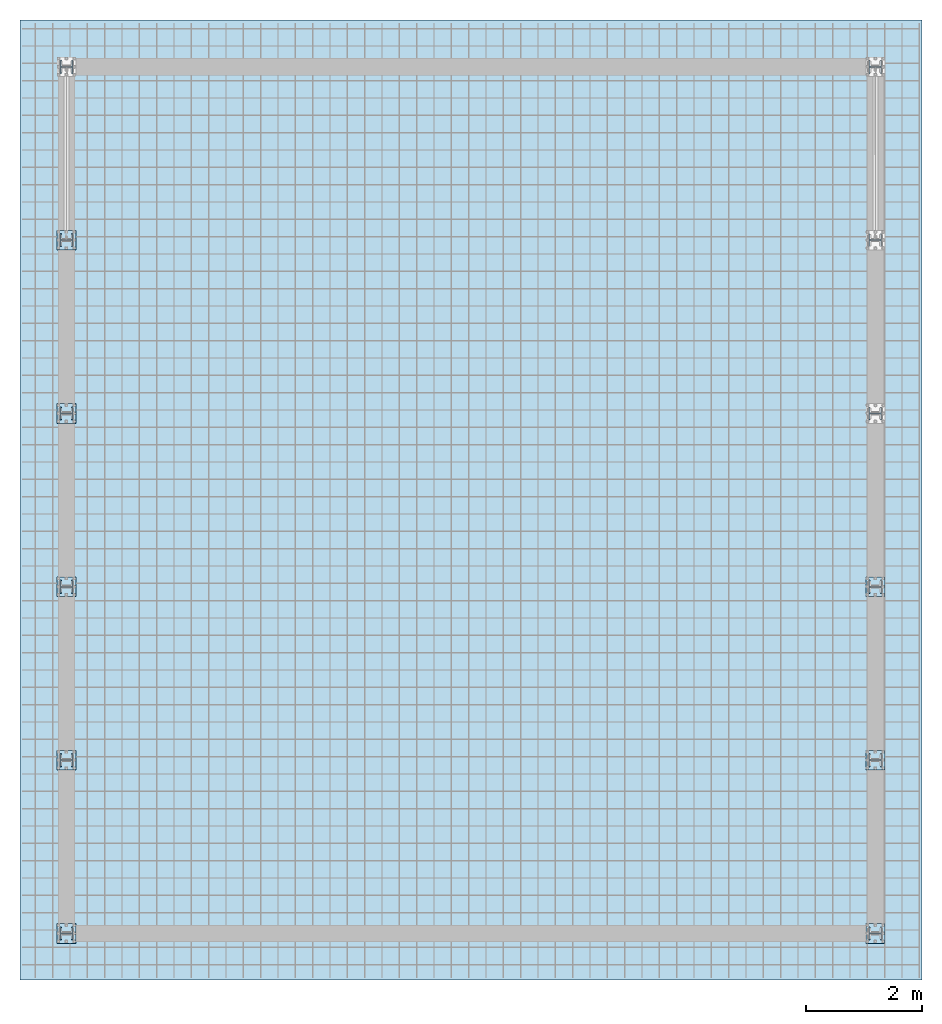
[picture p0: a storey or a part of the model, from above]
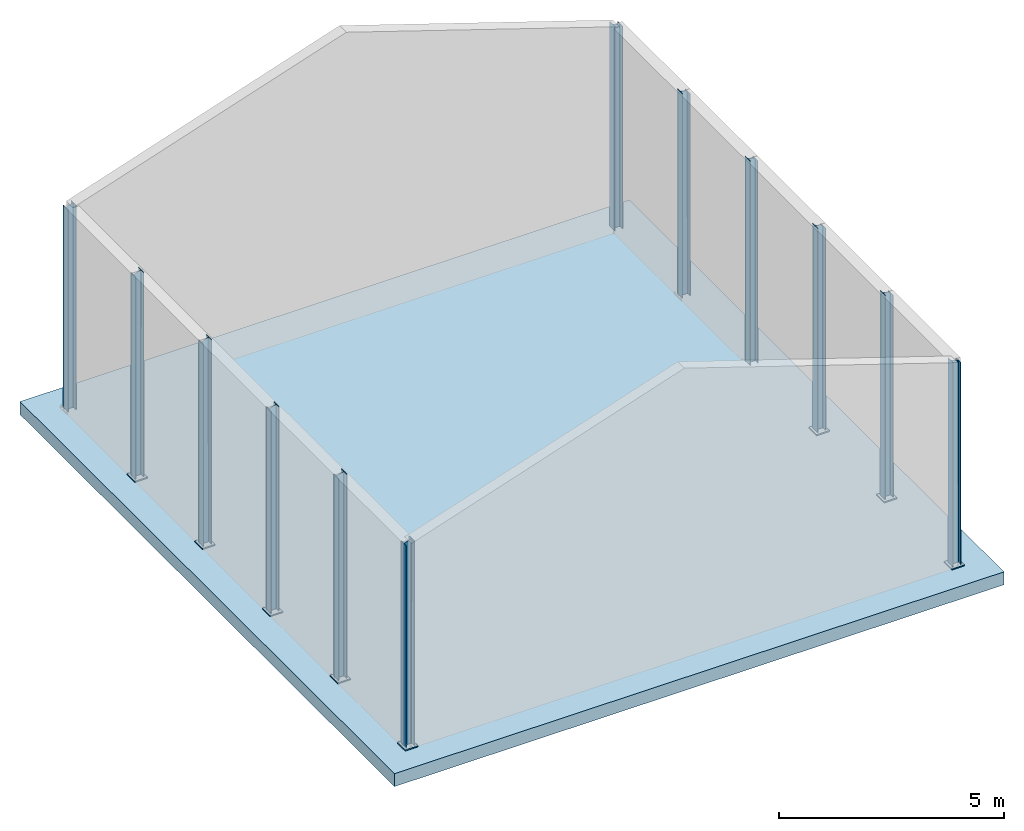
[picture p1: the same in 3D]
Properties of the parts of a building model (IFC4), part 1 of 2

# File
Description: ViewDefinition [CoordinationView]
Made in: IFC file generated by ModeSt (Tecnisoft s.a.s.)

# IfcBuildingStorey (2)
In: Capannone
Name | Elevation (m)
Storey 0 | 0
Storey 1 | 5.55

# IfcBeam: 3 IPE240 (96)
In: Storey 1
Type - PredefinedType: BEAM; Material: Acciaio
Description: 3 IPE240 - Acciaio
Pset_BeamCommon - LoadBearing: yes
BaseQuantities - ?: 0.00371848 m2
Name | BaseQuantities, ? (m3) | BaseQuantities, ? (m)
103 | 0.00313125 | 0.842077
104 | 0.00313125 | 0.842077
101 | 0.00313125 | 0.842077
102 | 0.00313125 | 0.842077
105 | 0.00313125 | 0.842077
106 | 0.00313125 | 0.842077
145 | 0.00313124 | 0.842077
144 | 0.00313124 | 0.842077
143 | 0.00313124 | 0.842077
142 | 0.00313124 | 0.842077
7 x 106 | 0.00391406 | 1.0526
7 x 145 | 0.00391406 | 1.0526
7 x 101 | 0.00391406 | 1.0526
7 x 102 | 0.00391406 | 1.0526
7 x 103 | 0.00391406 | 1.0526
7 x 142 | 0.00391406 | 1.0526
7 x 104 | 0.00391406 | 1.0526
7 x 143 | 0.00391406 | 1.0526
7 x 105 | 0.00391406 | 1.0526
7 x 144 | 0.00391406 | 1.0526
141 | 0.00313124 | 0.842077
140 | 0.00313124 | 0.842077
7 x 141 | 0.00391406 | 1.0526
7 x 140 | 0.00391406 | 1.0526

# IfcBuildingElementProxy: 1 Piatto 50x5 (16)
In: Storey 1
Type - PredefinedType: MEMBER; Material: Acciaio
Description: 1 Piatto 50x5 - Acciaio
Pset_MemberCommon - LoadBearing: yes
BaseQuantities - ?: 0.00025 m2
Name | BaseQuantities, ? (m3) | BaseQuantities, ? (m)
139 | 0.000916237 | 3.66495
135 | 0.000794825 | 3.1793
132 | 0.000794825 | 3.1793
137 | 0.000916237 | 3.66495
126 | 0.000916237 | 3.66495
129 | 0.000916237 | 3.66495
131 | 0.000916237 | 3.66495
127 | 0.000916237 | 3.66495
124 | 0.000916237 | 3.66495
130 | 0.000916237 | 3.66495
134 | 0.000916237 | 3.66495
133 | 0.000794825 | 3.1793
138 | 0.000794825 | 3.1793
136 | 0.000916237 | 3.66495
128 | 0.000916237 | 3.66495
125 | 0.000916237 | 3.66495

# IfcBuildingElementProxy: 2 L45x4 (4)
In: Storey 0
Type - PredefinedType: MEMBER; Material: Acciaio
Description: 2 L45x4 - Acciaio
Pset_MemberCommon - LoadBearing: yes
BaseQuantities - ?: 0.000344 m2; ?: 0.00217027 m3; ?: 6.30892 m
Name
200
186
147
161

# IfcBuildingElementProxy: 4 RHS100x50x3.2 (119)
In: Storey 1
Type - PredefinedType: MEMBER; Material: Acciaio
Description: 4 RHS100x50x3.2 - Acciaio
Pset_MemberCommon - LoadBearing: yes
BaseQuantities - ?: 0.00091904 m2
Name | BaseQuantities, ? (m3) | BaseQuantities, ? (m)
2 x 115 | 0.000560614 | 0.61
2 x 121 | 0.000560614 | 0.61
2 x 109 | 0.000560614 | 0.61
2 x 114 | 0.000560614 | 0.61
2 x 113 | 0.000560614 | 0.61
2 x 112 | 0.000560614 | 0.61
2 x 111 | 0.000560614 | 0.61
2 x 110 | 0.000560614 | 0.61
2 x 107 | 0.000560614 | 0.61
2 x 108 | 0.000560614 | 0.61
2 x 116 | 0.000560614 | 0.61
5 x 107 | 0.00275712 | 3
2 x 117 | 0.000560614 | 0.61
2 x 118 | 0.000560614 | 0.61
2 x 119 | 0.000560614 | 0.61
2 x 120 | 0.000560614 | 0.61
2 x 123 | 0.000560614 | 0.61
2 x 122 | 0.000560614 | 0.61
5 x 110 | 0.00275712 | 3
5 x 112 | 0.00275712 | 3
5 x 114 | 0.00275712 | 3
5 x 123 | 0.00275712 | 3
5 x 122 | 0.00275712 | 3
5 x 108 | 0.00275712 | 3
5 x 115 | 0.00275712 | 3
5 x 113 | 0.00275712 | 3
5 x 111 | 0.00275712 | 3
5 x 109 | 0.00275712 | 3
5 x 116 | 0.00275712 | 3
5 x 117 | 0.00275712 | 3
5 x 118 | 0.00275712 | 3
5 x 119 | 0.00275712 | 3
5 x 120 | 0.00275712 | 3
5 x 121 | 0.00275712 | 3

# IfcColumn: 5 HEA220 (12)
In: Storey 0
Type - PredefinedType: COLUMN; Material: Acciaio
Description: 5 HEA220 - Acciaio
Pset_ColumnCommon - LoadBearing: yes
BaseQuantities - ?: 0.006156 m2; ?: 0.0341658 m3; ?: 5.55 m
Name
10
4
6
8
9
7
5
3
12
11
1
2

# IfcFastener: Collegamenti -1142_-1128 -1143_-1130 -1144_-1132 -1145_-1134 -1146_-1136 -1147_-1138 (108)
In: Storey 1
Type - PredefinedType: WELD
Name | Description
48 x Collegamenti -1142_-1128 -1143_-1130 -1144_-1132 -1145_-1134 -1146_-1136 -1147_-1138 | 13x13
60 x Collegamenti -1142_-1128 -1143_-1130 -1144_-1132 -1145_-1134 -1146_-1136 -1147_-1138 | 10x10

# IfcFastener: Collegamenti 0001_0101 0002_0102 0003_0103 0004_0104 0005_0105 0006_0106 0007_0107 0008_0108 0009_0109 0010_0110 0011_0111 0012_0112 (192)
In: Storey 0
Type - PredefinedType: WELD
Description: 16x16

# IfcFastener: Collegamenti 0101_0001 0103_0003 0105_0005 0107_0007 0109_0009 0111_0011 (96)
In: Storey 1
Type - PredefinedType: WELD
Description: 10x10

# IfcFastener: Collegamenti 0102_0002 0104_0004 0106_0006 0108_0008 0110_0010 0112_0012 (96)
In: Storey 1
Type - PredefinedType: WELD
Description: 10x10

# IfcFastener: Collegamento -1055_-1089 (2)
In: Storey 1
Type - PredefinedType: WELD
Description: 7x7

# IfcFastener: Collegamento -1055_0111 (2)
In: Storey 1
Type - PredefinedType: WELD
Description: 7x7

# IfcFastener: Collegamento -1056_-1090 (2)
In: Storey 1
Type - PredefinedType: WELD
Description: 7x7

# IfcFastener: Collegamento -1056_0112 (2)
In: Storey 1
Type - PredefinedType: WELD
Description: 7x7

# IfcFastener: Collegamento -1057_-1087 (2)
In: Storey 1
Type - PredefinedType: WELD
Description: 7x7

# IfcFastener: Collegamento -1057_0109 (2)
In: Storey 1
Type - PredefinedType: WELD
Description: 7x7

# IfcFastener: Collegamento -1058_-1088 (2)
In: Storey 1
Type - PredefinedType: WELD
Description: 7x7

# IfcFastener: Collegamento -1058_0110 (2)
In: Storey 1
Type - PredefinedType: WELD
Description: 7x7

# IfcFastener: Collegamento -1087_-1057 (2)
In: Storey 1
Type - PredefinedType: WELD
Description: 7x7

# IfcFastener: Collegamento -1087_-1121 (2)
In: Storey 1
Type - PredefinedType: WELD
Description: 7x7

# IfcFastener: Collegamento -1088_-1058 (2)
In: Storey 1
Type - PredefinedType: WELD
Description: 7x7

# IfcFastener: Collegamento -1088_-1122 (2)
In: Storey 1
Type - PredefinedType: WELD
Description: 7x7

# IfcFastener: Collegamento -1089_-1055 (2)
In: Storey 1
Type - PredefinedType: WELD
Description: 7x7

# IfcFastener: Collegamento -1089_-1119 (2)
In: Storey 1
Type - PredefinedType: WELD
Description: 7x7

# IfcFastener: Collegamento -1090_-1056 (2)
In: Storey 1
Type - PredefinedType: WELD
Description: 7x7

# IfcFastener: Collegamento -1090_-1120 (2)
In: Storey 1
Type - PredefinedType: WELD
Description: 7x7

# IfcFastener: Collegamento -1119_-1089 (2)
In: Storey 1
Type - PredefinedType: WELD
Description: 7x7

# IfcFastener: Collegamento -1119_-1147 (2)
In: Storey 1
Type - PredefinedType: WELD
Description: 7x7

# IfcFastener: Collegamento -1120_-1090 (2)
In: Storey 1
Type - PredefinedType: WELD
Description: 7x7

# IfcFastener: Collegamento -1120_-1147 (2)
In: Storey 1
Type - PredefinedType: WELD
Description: 7x7

# IfcFastener: Collegamento -1121_-1087 (2)
In: Storey 1
Type - PredefinedType: WELD
Description: 7x7

# IfcFastener: Collegamento -1121_-1146 (2)
In: Storey 1
Type - PredefinedType: WELD
Description: 7x7

# IfcFastener: Collegamento -1122_-1088 (2)
In: Storey 1
Type - PredefinedType: WELD
Description: 7x7

# IfcFastener: Collegamento -1122_-1146 (2)
In: Storey 1
Type - PredefinedType: WELD
Description: 7x7

# IfcFastener: Collegamento -1146_-1121 (2)
In: Storey 1
Type - PredefinedType: WELD
Description: 7x7

# IfcFastener: Collegamento -1146_-1122 (2)
In: Storey 1
Type - PredefinedType: WELD
Description: 7x7

# IfcFastener: Collegamento -1147_-1119 (2)
In: Storey 1
Type - PredefinedType: WELD
Description: 7x7

# IfcFastener: Collegamento -1147_-1120 (2)
In: Storey 1
Type - PredefinedType: WELD
Description: 7x7

# IfcFastener: Collegamento 0009_0111 (2)
In: Storey 0
Type - PredefinedType: WELD
Description: 5x5

# IfcFastener: Collegamento 0010_0112 (2)
In: Storey 0
Type - PredefinedType: WELD
Description: 5x5

# IfcFastener: Collegamento 0011_0109 (2)
In: Storey 0
Type - PredefinedType: WELD
Description: 5x5

# IfcFastener: Collegamento 0012_0110 (2)
In: Storey 0
Type - PredefinedType: WELD
Description: 5x5

# IfcFastener: Collegamento 0109_-1057 (2)
In: Storey 1
Type - PredefinedType: WELD
Description: 7x7

# IfcFastener: Collegamento 0109_0011 (2)
In: Storey 1
Type - PredefinedType: WELD
Description: 5x5

# IfcFastener: Collegamento 0110_-1058 (2)
In: Storey 1
Type - PredefinedType: WELD
Description: 7x7

# IfcFastener: Collegamento 0110_0012 (2)
In: Storey 1
Type - PredefinedType: WELD
Description: 5x5

# IfcFastener: Collegamento 0111_-1055 (2)
In: Storey 1
Type - PredefinedType: WELD
Description: 7x7

# IfcFastener: Collegamento 0111_0009 (2)
In: Storey 1
Type - PredefinedType: WELD
Description: 5x5

# IfcFastener: Collegamento 0112_-1056 (2)
In: Storey 1
Type - PredefinedType: WELD
Description: 7x7

# IfcFastener: Collegamento 0112_0010 (2)
In: Storey 1
Type - PredefinedType: WELD
Description: 5x5

# IfcFooting: 1 Platea di fondazione
In: Storey 0
Type - PredefinedType: STRIP_FOOTING
Description: 1 Platea di fondazione; Material: Calcestruzzo classe C25/30 0.35 m
Pset_WallCommon - LoadBearing: yes
BaseQuantities - ?: 90.7761 m3

# IfcMechanicalFastener: Collegamenti -1142_-1128 -1143_-1130 -1144_-1132 -1145_-1134 -1146_-1136 -1147_-1138 (144)
In: Storey 1
Type - PredefinedType: BOLT
Name | Description | NominalDiameter (m)
44 x Collegamenti -1142_-1128 -1143_-1130 -1144_-1132 -1145_-1134 -1146_-1136 -1147_-1138 | M16 | 0.016
36 x Collegamenti -1142_-1128 -1143_-1130 -1144_-1132 -1145_-1134 -1146_-1136 -1147_-1138 | M32 | 0.032
4 x Collegamenti -1142_-1128 -1143_-1130 -1144_-1132 -1145_-1134 -1146_-1136 -1147_-1138 | M16 | 0.0159996
24 x Collegamenti -1142_-1128 -1143_-1130 -1144_-1132 -1145_-1134 -1146_-1136 -1147_-1138 | M16 | 0.0159995
36 x Collegamenti -1142_-1128 -1143_-1130 -1144_-1132 -1145_-1134 -1146_-1136 -1147_-1138 | M16 | 0.0159993

# IfcMechanicalFastener: Collegamenti 0001_0101 0002_0102 0003_0103 0004_0104 0005_0105 0006_0106 0007_0107 0008_0108 0009_0109 0010_0110 0011_0111 0012_0112 (480)
In: Storey 0
Type - PredefinedType: BOLT
Name | Description | NominalDiameter (m)
48 x Collegamenti 0001_0101 0002_0102 0003_0103 0004_0104 0005_0105 0006_0106 0007_0107 0008_0108 0009_0109 0010_0110 0011_0111 0012_0112 | M22 | 0.022
192 x Collegamenti 0001_0101 0002_0102 0003_0103 0004_0104 0005_0105 0006_0106 0007_0107 0008_0108 0009_0109 0010_0110 0011_0111 0012_0112 | M44 | 0.044
36 x Collegamenti 0001_0101 0002_0102 0003_0103 0004_0104 0005_0105 0006_0106 0007_0107 0008_0108 0009_0109 0010_0110 0011_0111 0012_0112 | M22 | 0.0219999
168 x Collegamenti 0001_0101 0002_0102 0003_0103 0004_0104 0005_0105 0006_0106 0007_0107 0008_0108 0009_0109 0010_0110 0011_0111 0012_0112 | M22 | 0.0219998
36 x Collegamenti 0001_0101 0002_0102 0003_0103 0004_0104 0005_0105 0006_0106 0007_0107 0008_0108 0009_0109 0010_0110 0011_0111 0012_0112 | M22 | 0.0219994

# IfcMechanicalFastener: Collegamenti 0101_0001 0103_0003 0105_0005 0107_0007 0109_0009 0111_0011 (192)
In: Storey 1
Type - PredefinedType: BOLT
Name | Description | NominalDiameter (m)
80 x Collegamenti 0101_0001 0103_0003 0105_0005 0107_0007 0109_0009 0111_0011 | M12 | 0.012
48 x Collegamenti 0101_0001 0103_0003 0105_0005 0107_0007 0109_0009 0111_0011 | M24 | 0.024
64 x Collegamenti 0101_0001 0103_0003 0105_0005 0107_0007 0109_0009 0111_0011 | M12 | 0.0119998

# IfcMechanicalFastener: Collegamenti 0102_0002 0104_0004 0106_0006 0108_0008 0110_0010 0112_0012 (192)
In: Storey 1
Type - PredefinedType: BOLT
Name | Description | NominalDiameter (m)
52 x Collegamenti 0102_0002 0104_0004 0106_0006 0108_0008 0110_0010 0112_0012 | M12 | 0.012
30 x Collegamenti 0102_0002 0104_0004 0106_0006 0108_0008 0110_0010 0112_0012 | M12 | 0.0119995
48 x Collegamenti 0102_0002 0104_0004 0106_0006 0108_0008 0110_0010 0112_0012 | M24 | 0.024
2 x Collegamenti 0102_0002 0104_0004 0106_0006 0108_0008 0110_0010 0112_0012 | M12 | 0.0119996
4 x Collegamenti 0102_0002 0104_0004 0106_0006 0108_0008 0110_0010 0112_0012 | M12 | 0.0119998
4 x Collegamenti 0102_0002 0104_0004 0106_0006 0108_0008 0110_0010 0112_0012 | M12 | 0.0119997
16 x Collegamenti 0102_0002 0104_0004 0106_0006 0108_0008 0110_0010 0112_0012 | M12 | 0.0120001
30 x Collegamenti 0102_0002 0104_0004 0106_0006 0108_0008 0110_0010 0112_0012 | M12 | 0.0119993
6 x Collegamenti 0102_0002 0104_0004 0106_0006 0108_0008 0110_0010 0112_0012 | M12 | 0.0119994

# IfcMechanicalFastener: Collegamento -1055_-1089 (8)
In: Storey 1
Type - PredefinedType: BOLT
Name | Description | NominalDiameter (m)
2 x Collegamento -1055_-1089 | M12 | 0.0119996
2 x Collegamento -1055_-1089 | M12 | 0.012
2 x Collegamento -1055_-1089 | M24 | 0.024
2 x Collegamento -1055_-1089 | M12 | 0.0119992

# IfcMechanicalFastener: Collegamento -1055_0111 (8)
In: Storey 1
Type - PredefinedType: BOLT
Name | Description | NominalDiameter (m)
4 x Collegamento -1055_0111 | M12 | 0.0119997
2 x Collegamento -1055_0111 | M12 | 0.012
2 x Collegamento -1055_0111 | M24 | 0.024

# IfcMechanicalFastener: Collegamento -1056_-1090 (8)
In: Storey 1
Type - PredefinedType: BOLT
Name | Description | NominalDiameter (m)
2 x Collegamento -1056_-1090 | M12 | 0.0119996
2 x Collegamento -1056_-1090 | M12 | 0.012
2 x Collegamento -1056_-1090 | M24 | 0.024
2 x Collegamento -1056_-1090 | M12 | 0.0119997

# IfcMechanicalFastener: Collegamento -1056_0112 (8)
In: Storey 1
Type - PredefinedType: BOLT
Name | Description | NominalDiameter (m)
2 x Collegamento -1056_0112 | M12 | 0.0119993
2 x Collegamento -1056_0112 | M12 | 0.012
2 x Collegamento -1056_0112 | M24 | 0.024
Collegamento -1056_0112 | M12 | 0.0119997
Collegamento -1056_0112 | M12 | 0.0119992

# IfcMechanicalFastener: Collegamento -1057_-1087 (8)
In: Storey 1
Type - PredefinedType: BOLT
Name | Description | NominalDiameter (m)
Collegamento -1057_-1087 | M12 | 0.0119996
2 x Collegamento -1057_-1087 | M12 | 0.012
Collegamento -1057_-1087 | M12 | 0.0119997
2 x Collegamento -1057_-1087 | M24 | 0.024
Collegamento -1057_-1087 | M12 | 0.0119993
Collegamento -1057_-1087 | M12 | 0.0119992

# IfcMechanicalFastener: Collegamento -1057_0109 (8)
In: Storey 1
Type - PredefinedType: BOLT
Name | Description | NominalDiameter (m)
2 x Collegamento -1057_0109 | M12 | 0.0119998
2 x Collegamento -1057_0109 | M12 | 0.012
2 x Collegamento -1057_0109 | M24 | 0.024
2 x Collegamento -1057_0109 | M12 | 0.0119997

# IfcMechanicalFastener: Collegamento -1058_-1088 (8)
In: Storey 1
Type - PredefinedType: BOLT
Name | Description | NominalDiameter (m)
2 x Collegamento -1058_-1088 | M12 | 0.0119995
2 x Collegamento -1058_-1088 | M12 | 0.012
2 x Collegamento -1058_-1088 | M24 | 0.024
2 x Collegamento -1058_-1088 | M12 | 0.0119994

# IfcMechanicalFastener: Collegamento -1058_0110 (8)
In: Storey 1
Type - PredefinedType: BOLT
Name | Description | NominalDiameter (m)
2 x Collegamento -1058_0110 | M12 | 0.0119997
2 x Collegamento -1058_0110 | M12 | 0.012
2 x Collegamento -1058_0110 | M24 | 0.024
2 x Collegamento -1058_0110 | M12 | 0.0119992

# IfcMechanicalFastener: Collegamento -1087_-1057 (8)
In: Storey 1
Type - PredefinedType: BOLT
Name | Description | NominalDiameter (m)
2 x Collegamento -1087_-1057 | M12 | 0.0119996
2 x Collegamento -1087_-1057 | M12 | 0.012
2 x Collegamento -1087_-1057 | M24 | 0.024
2 x Collegamento -1087_-1057 | M12 | 0.0119997

# IfcMechanicalFastener: Collegamento -1087_-1121 (8)
In: Storey 1
Type - PredefinedType: BOLT
Name | Description | NominalDiameter (m)
2 x Collegamento -1087_-1121 | M12 | 0.0119996
2 x Collegamento -1087_-1121 | M12 | 0.012
2 x Collegamento -1087_-1121 | M24 | 0.024
2 x Collegamento -1087_-1121 | M12 | 0.0119997

# IfcMechanicalFastener: Collegamento -1088_-1058 (8)
In: Storey 1
Type - PredefinedType: BOLT
Name | Description | NominalDiameter (m)
2 x Collegamento -1088_-1058 | M12 | 0.0119994
2 x Collegamento -1088_-1058 | M12 | 0.012
2 x Collegamento -1088_-1058 | M24 | 0.024
Collegamento -1088_-1058 | M12 | 0.0119992
Collegamento -1088_-1058 | M12 | 0.0119995

# IfcMechanicalFastener: Collegamento -1088_-1122 (8)
In: Storey 1
Type - PredefinedType: BOLT
Name | Description | NominalDiameter (m)
2 x Collegamento -1088_-1122 | M12 | 0.0119993
2 x Collegamento -1088_-1122 | M12 | 0.012
2 x Collegamento -1088_-1122 | M24 | 0.024
Collegamento -1088_-1122 | M12 | 0.0119989
Collegamento -1088_-1122 | M12 | 0.0119994

# IfcMechanicalFastener: Collegamento -1089_-1055 (8)
In: Storey 1
Type - PredefinedType: BOLT
Name | Description | NominalDiameter (m)
4 x Collegamento -1089_-1055 | M12 | 0.0119997
2 x Collegamento -1089_-1055 | M12 | 0.012
2 x Collegamento -1089_-1055 | M24 | 0.024

# IfcMechanicalFastener: Collegamento -1089_-1119 (8)
In: Storey 1
Type - PredefinedType: BOLT
Name | Description | NominalDiameter (m)
2 x Collegamento -1089_-1119 | M12 | 0.0119996
2 x Collegamento -1089_-1119 | M12 | 0.012
2 x Collegamento -1089_-1119 | M24 | 0.024
2 x Collegamento -1089_-1119 | M12 | 0.0119997

# IfcMechanicalFastener: Collegamento -1090_-1056 (8)
In: Storey 1
Type - PredefinedType: BOLT
Name | Description | NominalDiameter (m)
4 x Collegamento -1090_-1056 | M12 | 0.0119997
2 x Collegamento -1090_-1056 | M12 | 0.012
2 x Collegamento -1090_-1056 | M24 | 0.024

# IfcMechanicalFastener: Collegamento -1090_-1120 (8)
In: Storey 1
Type - PredefinedType: BOLT
Name | Description | NominalDiameter (m)
2 x Collegamento -1090_-1120 | M12 | 0.0119995
2 x Collegamento -1090_-1120 | M12 | 0.012
2 x Collegamento -1090_-1120 | M24 | 0.024
2 x Collegamento -1090_-1120 | M12 | 0.0119994

# IfcMechanicalFastener: Collegamento -1119_-1089 (8)
In: Storey 1
Type - PredefinedType: BOLT
Name | Description | NominalDiameter (m)
2 x Collegamento -1119_-1089 | M12 | 0.0119994
2 x Collegamento -1119_-1089 | M12 | 0.012
2 x Collegamento -1119_-1089 | M24 | 0.024
2 x Collegamento -1119_-1089 | M12 | 0.0119996

# IfcMechanicalFastener: Collegamento -1119_-1147 (8)
In: Storey 1
Type - PredefinedType: BOLT
Name | Description | NominalDiameter (m)
4 x Collegamento -1119_-1147 | M12 | 0.0119997
2 x Collegamento -1119_-1147 | M12 | 0.012
2 x Collegamento -1119_-1147 | M24 | 0.024

# IfcMechanicalFastener: Collegamento -1120_-1090 (8)
In: Storey 1
Type - PredefinedType: BOLT
Name | Description | NominalDiameter (m)
2 x Collegamento -1120_-1090 | M12 | 0.0119995
2 x Collegamento -1120_-1090 | M12 | 0.012
2 x Collegamento -1120_-1090 | M24 | 0.024
2 x Collegamento -1120_-1090 | M12 | 0.0119994

# IfcMechanicalFastener: Collegamento -1120_-1147 (8)
In: Storey 1
Type - PredefinedType: BOLT
Name | Description | NominalDiameter (m)
2 x Collegamento -1120_-1147 | M12 | 0.0119994
2 x Collegamento -1120_-1147 | M12 | 0.012
2 x Collegamento -1120_-1147 | M24 | 0.024
2 x Collegamento -1120_-1147 | M12 | 0.0119995

# IfcMechanicalFastener: Collegamento -1121_-1087 (8)
In: Storey 1
Type - PredefinedType: BOLT
Name | Description | NominalDiameter (m)
2 x Collegamento -1121_-1087 | M12 | 0.0119997
2 x Collegamento -1121_-1087 | M12 | 0.012
2 x Collegamento -1121_-1087 | M24 | 0.024
Collegamento -1121_-1087 | M12 | 0.0119994
Collegamento -1121_-1087 | M12 | 0.0119996

# IfcMechanicalFastener: Collegamento -1121_-1146 (8)
In: Storey 1
Type - PredefinedType: BOLT
Name | Description | NominalDiameter (m)
2 x Collegamento -1121_-1146 | M12 | 0.0119997
2 x Collegamento -1121_-1146 | M12 | 0.012
2 x Collegamento -1121_-1146 | M24 | 0.024
2 x Collegamento -1121_-1146 | M12 | 0.0119996

# IfcMechanicalFastener: Collegamento -1122_-1088 (8)
In: Storey 1
Type - PredefinedType: BOLT
Name | Description | NominalDiameter (m)
2 x Collegamento -1122_-1088 | M12 | 0.0119995
2 x Collegamento -1122_-1088 | M12 | 0.012
2 x Collegamento -1122_-1088 | M24 | 0.024
2 x Collegamento -1122_-1088 | M12 | 0.0119994

# IfcMechanicalFastener: Collegamento -1122_-1146 (8)
In: Storey 1
Type - PredefinedType: BOLT
Name | Description | NominalDiameter (m)
2 x Collegamento -1122_-1146 | M12 | 0.0119995
2 x Collegamento -1122_-1146 | M12 | 0.012
2 x Collegamento -1122_-1146 | M24 | 0.024
2 x Collegamento -1122_-1146 | M12 | 0.0119994

# IfcMechanicalFastener: Collegamento -1146_-1121 (8)
In: Storey 1
Type - PredefinedType: BOLT
Name | Description | NominalDiameter (m)
2 x Collegamento -1146_-1121 | M12 | 0.0119996
2 x Collegamento -1146_-1121 | M12 | 0.012
2 x Collegamento -1146_-1121 | M24 | 0.024
2 x Collegamento -1146_-1121 | M12 | 0.0119997

# IfcMechanicalFastener: Collegamento -1146_-1122 (8)
In: Storey 1
Type - PredefinedType: BOLT
Name | Description | NominalDiameter (m)
4 x Collegamento -1146_-1122 | M12 | 0.0119997
2 x Collegamento -1146_-1122 | M12 | 0.012
2 x Collegamento -1146_-1122 | M24 | 0.024

# IfcMechanicalFastener: Collegamento -1147_-1119 (8)
In: Storey 1
Type - PredefinedType: BOLT
Name | Description | NominalDiameter (m)
2 x Collegamento -1147_-1119 | M12 | 0.0119997
2 x Collegamento -1147_-1119 | M12 | 0.012
2 x Collegamento -1147_-1119 | M24 | 0.024
2 x Collegamento -1147_-1119 | M12 | 0.0119996

# IfcMechanicalFastener: Collegamento -1147_-1120 (8)
In: Storey 1
Type - PredefinedType: BOLT
Name | Description | NominalDiameter (m)
2 x Collegamento -1147_-1120 | M12 | 0.0119997
2 x Collegamento -1147_-1120 | M12 | 0.012
2 x Collegamento -1147_-1120 | M24 | 0.024
Collegamento -1147_-1120 | M12 | 0.0119994
Collegamento -1147_-1120 | M12 | 0.0119996

# IfcMechanicalFastener: Collegamento 0009_0111 (8)
In: Storey 0
Type - PredefinedType: BOLT
Name | Description | NominalDiameter (m)
4 x Collegamento 0009_0111 | M12 | 0.0119997
2 x Collegamento 0009_0111 | M12 | 0.012
2 x Collegamento 0009_0111 | M24 | 0.024

# IfcMechanicalFastener: Collegamento 0010_0112 (8)
In: Storey 0
Type - PredefinedType: BOLT
Name | Description | NominalDiameter (m)
2 x Collegamento 0010_0112 | M12 | 0.0119997
2 x Collegamento 0010_0112 | M12 | 0.012
2 x Collegamento 0010_0112 | M24 | 0.024
2 x Collegamento 0010_0112 | M12 | 0.0119998

# IfcMechanicalFastener: Collegamento 0011_0109 (8)
In: Storey 0
Type - PredefinedType: BOLT
Name | Description | NominalDiameter (m)
2 x Collegamento 0011_0109 | M12 | 0.0119998
2 x Collegamento 0011_0109 | M12 | 0.012
2 x Collegamento 0011_0109 | M24 | 0.024
2 x Collegamento 0011_0109 | M12 | 0.0119997

# IfcMechanicalFastener: Collegamento 0012_0110 (8)
In: Storey 0
Type - PredefinedType: BOLT
Name | Description | NominalDiameter (m)
4 x Collegamento 0012_0110 | M12 | 0.0119997
2 x Collegamento 0012_0110 | M12 | 0.012
2 x Collegamento 0012_0110 | M24 | 0.024

# IfcMechanicalFastener: Collegamento 0109_-1057 (8)
In: Storey 1
Type - PredefinedType: BOLT
Name | Description | NominalDiameter (m)
4 x Collegamento 0109_-1057 | M12 | 0.0119997
2 x Collegamento 0109_-1057 | M12 | 0.012
2 x Collegamento 0109_-1057 | M24 | 0.024

# IfcMechanicalFastener: Collegamento 0109_0011 (8)
In: Storey 1
Type - PredefinedType: BOLT
Name | Description | NominalDiameter (m)
2 x Collegamento 0109_0011 | M14 | 0.0139996
2 x Collegamento 0109_0011 | M14 | 0.014
2 x Collegamento 0109_0011 | M28 | 0.028
2 x Collegamento 0109_0011 | M14 | 0.0139997

# IfcMechanicalFastener: Collegamento 0110_-1058 (8)
In: Storey 1
Type - PredefinedType: BOLT
Name | Description | NominalDiameter (m)
2 x Collegamento 0110_-1058 | M12 | 0.0119993
2 x Collegamento 0110_-1058 | M12 | 0.012
2 x Collegamento 0110_-1058 | M24 | 0.024
2 x Collegamento 0110_-1058 | M12 | 0.0119995

# IfcMechanicalFastener: Collegamento 0110_0012 (8)
In: Storey 1
Type - PredefinedType: BOLT
Name | Description | NominalDiameter (m)
4 x Collegamento 0110_0012 | M14 | 0.0139997
2 x Collegamento 0110_0012 | M14 | 0.014
2 x Collegamento 0110_0012 | M28 | 0.028

# IfcMechanicalFastener: Collegamento 0111_-1055 (8)
In: Storey 1
Type - PredefinedType: BOLT
Name | Description | NominalDiameter (m)
4 x Collegamento 0111_-1055 | M12 | 0.0119997
2 x Collegamento 0111_-1055 | M12 | 0.012
2 x Collegamento 0111_-1055 | M24 | 0.024

# IfcMechanicalFastener: Collegamento 0111_0009 (8)
In: Storey 1
Type - PredefinedType: BOLT
Name | Description | NominalDiameter (m)
2 x Collegamento 0111_0009 | M12 | 0.0119998
2 x Collegamento 0111_0009 | M12 | 0.012
2 x Collegamento 0111_0009 | M24 | 0.024
2 x Collegamento 0111_0009 | M12 | 0.0119996

# IfcMechanicalFastener: Collegamento 0112_-1056 (8)
In: Storey 1
Type - PredefinedType: BOLT
Name | Description | NominalDiameter (m)
4 x Collegamento 0112_-1056 | M12 | 0.0119995
2 x Collegamento 0112_-1056 | M12 | 0.012
2 x Collegamento 0112_-1056 | M24 | 0.024

# IfcMechanicalFastener: Collegamento 0112_0010 (8)
In: Storey 1
Type - PredefinedType: BOLT
Name | Description | NominalDiameter (m)
2 x Collegamento 0112_0010 | M14 | 0.0139996
2 x Collegamento 0112_0010 | M14 | 0.014
2 x Collegamento 0112_0010 | M28 | 0.028
2 x Collegamento 0112_0010 | M14 | 0.0139997

# IfcPlate: Collegamenti -1142_-1128 -1143_-1130 -1144_-1132 -1145_-1134 -1146_-1136 -1147_-1138 (12)
In: Storey 1
Type - PredefinedType: SHEET

# IfcPlate: Collegamenti 0001_0101 0002_0102 0003_0103 0004_0104 0005_0105 0006_0106 0007_0107 0008_0108 0009_0109 0010_0110 0011_0111 0012_0112 (12)
In: Storey 0
Type - PredefinedType: SHEET

# IfcPlate: Collegamenti 0101_0001 0103_0003 0105_0005 0107_0007 0109_0009 0111_0011 (6)
In: Storey 1
Type - PredefinedType: SHEET

# IfcPlate: Collegamenti 0102_0002 0104_0004 0106_0006 0108_0008 0110_0010 0112_0012 (6)
In: Storey 1
Type - PredefinedType: SHEET

# IfcPlate: Collegamento -1055_-1089
In: Storey 1
Type - PredefinedType: SHEET

# IfcPlate: Collegamento -1055_0111
In: Storey 1
Type - PredefinedType: SHEET

# IfcPlate: Collegamento -1056_-1090
In: Storey 1
Type - PredefinedType: SHEET

# IfcPlate: Collegamento -1056_0112
In: Storey 1
Type - PredefinedType: SHEET

# IfcPlate: Collegamento -1057_-1087
In: Storey 1
Type - PredefinedType: SHEET

# IfcPlate: Collegamento -1057_0109
In: Storey 1
Type - PredefinedType: SHEET

# IfcPlate: Collegamento -1058_-1088
In: Storey 1
Type - PredefinedType: SHEET

# IfcPlate: Collegamento -1058_0110
In: Storey 1
Type - PredefinedType: SHEET

# IfcPlate: Collegamento -1087_-1057
In: Storey 1
Type - PredefinedType: SHEET

# IfcPlate: Collegamento -1087_-1121
In: Storey 1
Type - PredefinedType: SHEET

# IfcPlate: Collegamento -1088_-1058
In: Storey 1
Type - PredefinedType: SHEET

# IfcPlate: Collegamento -1088_-1122
In: Storey 1
Type - PredefinedType: SHEET

# IfcPlate: Collegamento -1089_-1055
In: Storey 1
Type - PredefinedType: SHEET

# IfcPlate: Collegamento -1089_-1119
In: Storey 1
Type - PredefinedType: SHEET

# IfcPlate: Collegamento -1090_-1056
In: Storey 1
Type - PredefinedType: SHEET

# IfcPlate: Collegamento -1090_-1120
In: Storey 1
Type - PredefinedType: SHEET

# IfcPlate: Collegamento -1119_-1089
In: Storey 1
Type - PredefinedType: SHEET

# IfcPlate: Collegamento -1119_-1147
In: Storey 1
Type - PredefinedType: SHEET

# IfcPlate: Collegamento -1120_-1090
In: Storey 1
Type - PredefinedType: SHEET

# IfcPlate: Collegamento -1120_-1147
In: Storey 1
Type - PredefinedType: SHEET

# IfcPlate: Collegamento -1121_-1087
In: Storey 1
Type - PredefinedType: SHEET

# IfcPlate: Collegamento -1121_-1146
In: Storey 1
Type - PredefinedType: SHEET

# IfcPlate: Collegamento -1122_-1088
In: Storey 1
Type - PredefinedType: SHEET

# IfcPlate: Collegamento -1122_-1146
In: Storey 1
Type - PredefinedType: SHEET

# IfcPlate: Collegamento -1146_-1121
In: Storey 1
Type - PredefinedType: SHEET

# IfcPlate: Collegamento -1146_-1122
In: Storey 1
Type - PredefinedType: SHEET

# IfcPlate: Collegamento -1147_-1119
In: Storey 1
Type - PredefinedType: SHEET

# IfcPlate: Collegamento -1147_-1120
In: Storey 1
Type - PredefinedType: SHEET

# IfcPlate: Collegamento 0009_0111
In: Storey 0
Type - PredefinedType: SHEET

# IfcPlate: Collegamento 0010_0112
In: Storey 0
Type - PredefinedType: SHEET

# IfcPlate: Collegamento 0011_0109
In: Storey 0
Type - PredefinedType: SHEET

# IfcPlate: Collegamento 0012_0110
In: Storey 0
Type - PredefinedType: SHEET

# IfcPlate: Collegamento 0109_-1057
In: Storey 1
Type - PredefinedType: SHEET

# IfcPlate: Collegamento 0109_0011
In: Storey 1
Type - PredefinedType: SHEET

# IfcPlate: Collegamento 0110_-1058
In: Storey 1
Type - PredefinedType: SHEET

# IfcPlate: Collegamento 0110_0012
In: Storey 1
Type - PredefinedType: SHEET

# IfcPlate: Collegamento 0111_-1055
In: Storey 1
Type - PredefinedType: SHEET

# IfcPlate: Collegamento 0111_0009
In: Storey 1
Type - PredefinedType: SHEET

# IfcPlate: Collegamento 0112_-1056
In: Storey 1
Type - PredefinedType: SHEET

# IfcPlate: Collegamento 0112_0010
In: Storey 1
Type - PredefinedType: SHEET

# IfcReinforcingBar (5)
In: Storey 0
Name | NominalDiameter (m) | CrossSectionArea (m2) | BarLength (m)
 | 0.022 | 0.00038013 | 0.333
 | 0.022 | 0.00038013 | 0.0257519
 | 0.022 | 0.00038013 | 0.066
 | 0.012 | 0.0001131 | 16.0372 | SteelGrade: B450C
 | 0.012 | 0.0001131 | 17.0422 | SteelGrade: B450C

# IfcSlab: 1 Copertura (112)
In: Storey 1
Type - PredefinedType: FLOOR; Material: Concrete
Description: 1 Copertura - Altezza solaio 0.100000 - Spessore cappa 0.000000 -
Pset_SlabCommon - LoadBearing: yes
BaseQuantities - ?: 0.1 m
Name | BaseQuantities, ? (m2) | BaseQuantities, ? (m3)
100 | 0.61 | 0.061
101 | 0.61 | 0.061
102 | 0.61 | 0.061
103 | 0.61 | 0.061
104 | 3 | 0.3
105 | -0.61 | -0.061
106 | -0.61 | -0.061
107 | -0.61 | -0.061
108 | 3 | 0.3
109 | 3 | 0.3
110 | -0.61 | -0.061
111 | 3 | 0.3
112 | 3 | 0.3
113 | 3 | 0.3
114 | 3 | 0.3
115 | -3 | -0.3
116 | -3 | -0.3
117 | -3 | -0.3
118 | -3 | -0.3
119 | -3 | -0.3
120 | -3 | -0.3
121 | 0.61 | 0.061
122 | -3 | -0.3
123 | -0.488 | -0.0488
124 | -0.61 | -0.061
125 | -0.61 | -0.061
126 | -0.61 | -0.061
127 | 3 | 0.3
128 | 0.61 | 0.061
129 | 3 | 0.3
130 | 3 | 0.3
131 | 3 | 0.3
132 | 3 | 0.3
133 | 0.61 | 0.061
134 | 0.488 | 0.0488
135 | 3 | 0.3
136 | 3 | 0.3
137 | -3 | -0.3
138 | -3 | -0.3
139 | -3 | -0.3
140 | -3 | -0.3
141 | 0.61 | 0.061
142 | 0.61 | 0.061
143 | 0.61 | 0.061
144 | 0.61 | 0.061
145 | 0.61 | 0.061
146 | -3 | -0.3
147 | 0.61 | 0.061
148 | 0.61 | 0.061
149 | 0.487999 | 0.0487999
150 | -0.487999 | -0.0487999
151 | -3 | -0.3
152 | -0.61 | -0.061
153 | -3 | -0.3
154 | 3 | 0.3
155 | 3 | 0.3
156 | 3 | 0.3
157 | -0.61 | -0.061
158 | -0.61 | -0.061
159 | 3 | 0.3
160 | 3 | 0.3
161 | 3 | 0.3
162 | -3 | -0.3
163 | 3 | 0.3
164 | -3 | -0.3
165 | -0.61 | -0.061
166 | -0.61 | -0.061
167 | -0.61 | -0.061
168 | -0.61 | -0.061
169 | 2.4 | 0.24
170 | -3 | -0.3
171 | 2.4 | 0.24
172 | 2.4 | 0.24
173 | 2.4 | 0.24
174 | 2.4 | 0.24
175 | -3 | -0.3
176 | -2.4 | -0.24
177 | -3 | -0.3
178 | -3 | -0.3
179 | -3 | -0.3
180 | 3 | 0.3
181 | -2.4 | -0.24
182 | -2.4 | -0.24
183 | 3 | 0.3
184 | 3 | 0.3
185 | 3 | 0.3
186 | 3 | 0.3
187 | 3 | 0.3
188 | 3 | 0.3
189 | -3 | -0.3
190 | -3 | -0.3
191 | -3 | -0.3
192 | -3 | -0.3
193 | -2.4 | -0.24
194 | -3 | -0.3
195 | -3 | -0.3
196 | -3 | -0.3
197 | -2.4 | -0.24
198 | -3 | -0.3
199 | -3 | -0.3
200 | -3 | -0.3
201 | -3 | -0.3
202 | -3 | -0.3
203 | -3 | -0.3
204 | -3 | -0.3
205 | 3 | 0.3
206 | 3 | 0.3
207 | 3 | 0.3
208 | 3 | 0.3
209 | 3 | 0.3
210 | 3 | 0.3
211 | 3 | 0.3

# IfcWall (12)
In: Storey 0
Material: Tamponatura
Pset_WallCommon - LoadBearing: yes
Name
102
112
101
111
108
103
104
105
106
107
110
109

# IfcReinforcingBarType, no part of this type: type
PredefinedType: MAIN; NominalDiameter: 0.022 m; CrossSectionArea: 0.00038013 m2; BarLength: 0.333 m; Material: Steel

# IfcReinforcingBarType, no part of this type: type
PredefinedType: MAIN; NominalDiameter: 0.022 m; CrossSectionArea: 0.00038013 m2; BarLength: 0.0257519 m; Material: Steel

# IfcReinforcingBarType, no part of this type: type
PredefinedType: MAIN; NominalDiameter: 0.022 m; CrossSectionArea: 0.00038013 m2; BarLength: 0.066 m; Material: Steel

# IfcReinforcingBarType, no part of this type: type
PredefinedType: MAIN; NominalDiameter: 0.012 m; CrossSectionArea: 0.0001131 m2; BarLength: 16.0372 m; Material: Steel

# IfcReinforcingBarType, no part of this type: type
PredefinedType: MAIN; NominalDiameter: 0.012 m; CrossSectionArea: 0.0001131 m2; BarLength: 17.0422 m; Material: Steel

# Material: Acciaio
Acciaio - Mass Density: 7850; Poisson Ratio: 0.3; Shear Modulus: 8000000000; Thermal Expansion Coefficient: 0.00001; Young Modulus: 20999999488

# Material: Acciaio
Acciaio - Mass Density: 7850; Poisson Ratio: 0.3; Shear Modulus: 8000000000; Thermal Expansion Coefficient: 0.00001; Young Modulus: 20999999488

# Material: Acciaio
Acciaio - Mass Density: 7850; Poisson Ratio: 0.3; Shear Modulus: 8000000000; Thermal Expansion Coefficient: 0.00001; Young Modulus: 20999999488

# Material: Acciaio
Acciaio - Mass Density: 7850; Poisson Ratio: 0.3; Shear Modulus: 8000000000; Thermal Expansion Coefficient: 0.00001; Young Modulus: 20999999488

# Material: Acciaio
Acciaio - Mass Density: 7850; Poisson Ratio: 0.3; Shear Modulus: 8000000000; Thermal Expansion Coefficient: 0.00001; Young Modulus: 20999999488

# Material: Acciaio
Acciaio - Mass Density: 7850; Poisson Ratio: 0.3; Shear Modulus: 8000000000; Thermal Expansion Coefficient: 0.00001; Young Modulus: 20999999488

# Material: Acciaio
Acciaio - Mass Density: 7850; Poisson Ratio: 0.3; Shear Modulus: 8000000000; Thermal Expansion Coefficient: 0.00001; Young Modulus: 20999999488

# Material: Acciaio
Acciaio - Mass Density: 7850; Poisson Ratio: 0.3; Shear Modulus: 8000000000; Thermal Expansion Coefficient: 0.00001; Young Modulus: 20999999488

# Material: Acciaio
Acciaio - Mass Density: 7850; Poisson Ratio: 0.3; Shear Modulus: 8000000000; Thermal Expansion Coefficient: 0.00001; Young Modulus: 20999999488

# Material: Acciaio
Acciaio - Mass Density: 7850; Poisson Ratio: 0.3; Shear Modulus: 8000000000; Thermal Expansion Coefficient: 0.00001; Young Modulus: 20999999488

# Material: Acciaio
Acciaio - Mass Density: 7850; Poisson Ratio: 0.3; Shear Modulus: 8000000000; Thermal Expansion Coefficient: 0.00001; Young Modulus: 20999999488

# Material: Acciaio
Acciaio - Mass Density: 7850; Poisson Ratio: 0.3; Shear Modulus: 8000000000; Thermal Expansion Coefficient: 0.00001; Young Modulus: 20999999488

# Material: Acciaio
Acciaio - Mass Density: 7850; Poisson Ratio: 0.3; Shear Modulus: 8000000000; Thermal Expansion Coefficient: 0.00001; Young Modulus: 20999999488

# Material: Acciaio
Acciaio - Mass Density: 7850; Poisson Ratio: 0.3; Shear Modulus: 8000000000; Thermal Expansion Coefficient: 0.00001; Young Modulus: 20999999488

# Material: Acciaio
Acciaio - Mass Density: 7850; Poisson Ratio: 0.3; Shear Modulus: 8000000000; Thermal Expansion Coefficient: 0.00001; Young Modulus: 20999999488

# Material: Acciaio
Acciaio - Mass Density: 7850; Poisson Ratio: 0.3; Shear Modulus: 8000000000; Thermal Expansion Coefficient: 0.00001; Young Modulus: 20999999488

# Material: Calcestruzzo classe C25/30
Calcestruzzo classe C25/30 - Mass Density: 2500; Poisson Ratio: 0.1; Shear Modulus: 1429420032; Thermal Expansion Coefficient: 0.00001; Young Modulus: 3144719872

# Material: Acciaio
Acciaio - Mass Density: 7850; Poisson Ratio: 0.3; Shear Modulus: 8000000000; Thermal Expansion Coefficient: 0.00001; Young Modulus: 20999999488

# Material: Acciaio
Acciaio - Mass Density: 7850; Poisson Ratio: 0.3; Shear Modulus: 8000000000; Thermal Expansion Coefficient: 0.00001; Young Modulus: 20999999488

# Material: Acciaio
Acciaio - Mass Density: 7850; Poisson Ratio: 0.3; Shear Modulus: 8000000000; Thermal Expansion Coefficient: 0.00001; Young Modulus: 20999999488

# Material: Acciaio
Acciaio - Mass Density: 7850; Poisson Ratio: 0.3; Shear Modulus: 8000000000; Thermal Expansion Coefficient: 0.00001; Young Modulus: 20999999488

# Material: Acciaio
Acciaio - Mass Density: 7850; Poisson Ratio: 0.3; Shear Modulus: 8000000000; Thermal Expansion Coefficient: 0.00001; Young Modulus: 20999999488

# Material: Acciaio
Acciaio - Mass Density: 7850; Poisson Ratio: 0.3; Shear Modulus: 8000000000; Thermal Expansion Coefficient: 0.00001; Young Modulus: 20999999488

# Material: Acciaio
Acciaio - Mass Density: 7850; Poisson Ratio: 0.3; Shear Modulus: 8000000000; Thermal Expansion Coefficient: 0.00001; Young Modulus: 20999999488

# Material: Acciaio
Acciaio - Mass Density: 7850; Poisson Ratio: 0.3; Shear Modulus: 8000000000; Thermal Expansion Coefficient: 0.00001; Young Modulus: 20999999488

# Material: Acciaio
Acciaio - Mass Density: 7850; Poisson Ratio: 0.3; Shear Modulus: 8000000000; Thermal Expansion Coefficient: 0.00001; Young Modulus: 20999999488

# Material: Acciaio
Acciaio - Mass Density: 7850; Poisson Ratio: 0.3; Shear Modulus: 8000000000; Thermal Expansion Coefficient: 0.00001; Young Modulus: 20999999488

# Material: Acciaio
Acciaio - Mass Density: 7850; Poisson Ratio: 0.3; Shear Modulus: 8000000000; Thermal Expansion Coefficient: 0.00001; Young Modulus: 20999999488

# Material: Acciaio
Acciaio - Mass Density: 7850; Poisson Ratio: 0.3; Shear Modulus: 8000000000; Thermal Expansion Coefficient: 0.00001; Young Modulus: 20999999488

# Material: Acciaio
Acciaio - Mass Density: 7850; Poisson Ratio: 0.3; Shear Modulus: 8000000000; Thermal Expansion Coefficient: 0.00001; Young Modulus: 20999999488

# Material: Acciaio
Acciaio - Mass Density: 7850; Poisson Ratio: 0.3; Shear Modulus: 8000000000; Thermal Expansion Coefficient: 0.00001; Young Modulus: 20999999488

# Material: Acciaio
Acciaio - Mass Density: 7850; Poisson Ratio: 0.3; Shear Modulus: 8000000000; Thermal Expansion Coefficient: 0.00001; Young Modulus: 20999999488

# Material: Acciaio
Acciaio - Mass Density: 7850; Poisson Ratio: 0.3; Shear Modulus: 8000000000; Thermal Expansion Coefficient: 0.00001; Young Modulus: 20999999488

# Material: Acciaio
Acciaio - Mass Density: 7850; Poisson Ratio: 0.3; Shear Modulus: 8000000000; Thermal Expansion Coefficient: 0.00001; Young Modulus: 20999999488

# Material: Acciaio
Acciaio - Mass Density: 7850; Poisson Ratio: 0.3; Shear Modulus: 8000000000; Thermal Expansion Coefficient: 0.00001; Young Modulus: 20999999488

# Material: Acciaio
Acciaio - Mass Density: 7850; Poisson Ratio: 0.3; Shear Modulus: 8000000000; Thermal Expansion Coefficient: 0.00001; Young Modulus: 20999999488

# Material: Acciaio
Acciaio - Mass Density: 7850; Poisson Ratio: 0.3; Shear Modulus: 8000000000; Thermal Expansion Coefficient: 0.00001; Young Modulus: 20999999488

# Material: Acciaio
Acciaio - Mass Density: 7850; Poisson Ratio: 0.3; Shear Modulus: 8000000000; Thermal Expansion Coefficient: 0.00001; Young Modulus: 20999999488

# Material: Acciaio
Acciaio - Mass Density: 7850; Poisson Ratio: 0.3; Shear Modulus: 8000000000; Thermal Expansion Coefficient: 0.00001; Young Modulus: 20999999488

# Material: Acciaio
Acciaio - Mass Density: 7850; Poisson Ratio: 0.3; Shear Modulus: 8000000000; Thermal Expansion Coefficient: 0.00001; Young Modulus: 20999999488

# Material: Acciaio
Acciaio - Mass Density: 7850; Poisson Ratio: 0.3; Shear Modulus: 8000000000; Thermal Expansion Coefficient: 0.00001; Young Modulus: 20999999488

# Material: Acciaio
Acciaio - Mass Density: 7850; Poisson Ratio: 0.3; Shear Modulus: 8000000000; Thermal Expansion Coefficient: 0.00001; Young Modulus: 20999999488

# Material: Acciaio
Acciaio - Mass Density: 7850; Poisson Ratio: 0.3; Shear Modulus: 8000000000; Thermal Expansion Coefficient: 0.00001; Young Modulus: 20999999488

# Material: Acciaio
Acciaio - Mass Density: 7850; Poisson Ratio: 0.3; Shear Modulus: 8000000000; Thermal Expansion Coefficient: 0.00001; Young Modulus: 20999999488

# Material: Acciaio
Acciaio - Mass Density: 7850; Poisson Ratio: 0.3; Shear Modulus: 8000000000; Thermal Expansion Coefficient: 0.00001; Young Modulus: 20999999488

# Material: Acciaio
Acciaio - Mass Density: 7850; Poisson Ratio: 0.3; Shear Modulus: 8000000000; Thermal Expansion Coefficient: 0.00001; Young Modulus: 20999999488

# Material: Acciaio
Acciaio - Mass Density: 7850; Poisson Ratio: 0.3; Shear Modulus: 8000000000; Thermal Expansion Coefficient: 0.00001; Young Modulus: 20999999488

# Material: Acciaio
Acciaio - Mass Density: 7850; Poisson Ratio: 0.3; Shear Modulus: 8000000000; Thermal Expansion Coefficient: 0.00001; Young Modulus: 20999999488

# Material: Acciaio
Acciaio - Mass Density: 7850; Poisson Ratio: 0.3; Shear Modulus: 8000000000; Thermal Expansion Coefficient: 0.00001; Young Modulus: 20999999488

# Material: Acciaio
Acciaio - Mass Density: 7850; Poisson Ratio: 0.3; Shear Modulus: 8000000000; Thermal Expansion Coefficient: 0.00001; Young Modulus: 20999999488

# Material: Acciaio
Acciaio - Mass Density: 7850; Poisson Ratio: 0.3; Shear Modulus: 8000000000; Thermal Expansion Coefficient: 0.00001; Young Modulus: 20999999488

# Material: Acciaio
Acciaio - Mass Density: 7850; Poisson Ratio: 0.3; Shear Modulus: 8000000000; Thermal Expansion Coefficient: 0.00001; Young Modulus: 20999999488

# Material: Acciaio
Acciaio - Mass Density: 7850; Poisson Ratio: 0.3; Shear Modulus: 8000000000; Thermal Expansion Coefficient: 0.00001; Young Modulus: 20999999488

# Material: Acciaio
Acciaio - Mass Density: 7850; Poisson Ratio: 0.3; Shear Modulus: 8000000000; Thermal Expansion Coefficient: 0.00001; Young Modulus: 20999999488

# Material: Acciaio
Acciaio - Mass Density: 7850; Poisson Ratio: 0.3; Shear Modulus: 8000000000; Thermal Expansion Coefficient: 0.00001; Young Modulus: 20999999488

# Material: Acciaio
Acciaio - Mass Density: 7850; Poisson Ratio: 0.3; Shear Modulus: 8000000000; Thermal Expansion Coefficient: 0.00001; Young Modulus: 20999999488

# Material: Acciaio
Acciaio - Mass Density: 7850; Poisson Ratio: 0.3; Shear Modulus: 8000000000; Thermal Expansion Coefficient: 0.00001; Young Modulus: 20999999488

# Material: Acciaio
Acciaio - Mass Density: 7850; Poisson Ratio: 0.3; Shear Modulus: 8000000000; Thermal Expansion Coefficient: 0.00001; Young Modulus: 20999999488

# Material: Acciaio
Acciaio - Mass Density: 7850; Poisson Ratio: 0.3; Shear Modulus: 8000000000; Thermal Expansion Coefficient: 0.00001; Young Modulus: 20999999488

# Material: Acciaio
Acciaio - Mass Density: 7850; Poisson Ratio: 0.3; Shear Modulus: 8000000000; Thermal Expansion Coefficient: 0.00001; Young Modulus: 20999999488

# Material: Acciaio
Acciaio - Mass Density: 7850; Poisson Ratio: 0.3; Shear Modulus: 8000000000; Thermal Expansion Coefficient: 0.00001; Young Modulus: 20999999488

# Material: Acciaio
Acciaio - Mass Density: 7850; Poisson Ratio: 0.3; Shear Modulus: 8000000000; Thermal Expansion Coefficient: 0.00001; Young Modulus: 20999999488

# Material: Acciaio
Acciaio - Mass Density: 7850; Poisson Ratio: 0.3; Shear Modulus: 8000000000; Thermal Expansion Coefficient: 0.00001; Young Modulus: 20999999488

# Material: Acciaio
Acciaio - Mass Density: 7850; Poisson Ratio: 0.3; Shear Modulus: 8000000000; Thermal Expansion Coefficient: 0.00001; Young Modulus: 20999999488

# Material: Acciaio
Acciaio - Mass Density: 7850; Poisson Ratio: 0.3; Shear Modulus: 8000000000; Thermal Expansion Coefficient: 0.00001; Young Modulus: 20999999488

# Material: Acciaio
Acciaio - Mass Density: 7850; Poisson Ratio: 0.3; Shear Modulus: 8000000000; Thermal Expansion Coefficient: 0.00001; Young Modulus: 20999999488

# Material: Acciaio
Acciaio - Mass Density: 7850; Poisson Ratio: 0.3; Shear Modulus: 8000000000; Thermal Expansion Coefficient: 0.00001; Young Modulus: 20999999488

# Material: Acciaio
Acciaio - Mass Density: 7850; Poisson Ratio: 0.3; Shear Modulus: 8000000000; Thermal Expansion Coefficient: 0.00001; Young Modulus: 20999999488

# Material: Acciaio
Acciaio - Mass Density: 7850; Poisson Ratio: 0.3; Shear Modulus: 8000000000; Thermal Expansion Coefficient: 0.00001; Young Modulus: 20999999488

# Material: Acciaio
Acciaio - Mass Density: 7850; Poisson Ratio: 0.3; Shear Modulus: 8000000000; Thermal Expansion Coefficient: 0.00001; Young Modulus: 20999999488

# Material: Acciaio
Acciaio - Mass Density: 7850; Poisson Ratio: 0.3; Shear Modulus: 8000000000; Thermal Expansion Coefficient: 0.00001; Young Modulus: 20999999488

# Material: Acciaio
Acciaio - Mass Density: 7850; Poisson Ratio: 0.3; Shear Modulus: 8000000000; Thermal Expansion Coefficient: 0.00001; Young Modulus: 20999999488

# Material: Acciaio
Acciaio - Mass Density: 7850; Poisson Ratio: 0.3; Shear Modulus: 8000000000; Thermal Expansion Coefficient: 0.00001; Young Modulus: 20999999488

# Material: Acciaio
Acciaio - Mass Density: 7850; Poisson Ratio: 0.3; Shear Modulus: 8000000000; Thermal Expansion Coefficient: 0.00001; Young Modulus: 20999999488

# Material: Acciaio
Acciaio - Mass Density: 7850; Poisson Ratio: 0.3; Shear Modulus: 8000000000; Thermal Expansion Coefficient: 0.00001; Young Modulus: 20999999488

# Material: Acciaio
Acciaio - Mass Density: 7850; Poisson Ratio: 0.3; Shear Modulus: 8000000000; Thermal Expansion Coefficient: 0.00001; Young Modulus: 20999999488

# Material: Acciaio
Acciaio - Mass Density: 7850; Poisson Ratio: 0.3; Shear Modulus: 8000000000; Thermal Expansion Coefficient: 0.00001; Young Modulus: 20999999488

# Material: Acciaio
Acciaio - Mass Density: 7850; Poisson Ratio: 0.3; Shear Modulus: 8000000000; Thermal Expansion Coefficient: 0.00001; Young Modulus: 20999999488

# Material: Acciaio
Acciaio - Mass Density: 7850; Poisson Ratio: 0.3; Shear Modulus: 8000000000; Thermal Expansion Coefficient: 0.00001; Young Modulus: 20999999488

# Material: Acciaio
Acciaio - Mass Density: 7850; Poisson Ratio: 0.3; Shear Modulus: 8000000000; Thermal Expansion Coefficient: 0.00001; Young Modulus: 20999999488

# Material: Acciaio
Acciaio - Mass Density: 7850; Poisson Ratio: 0.3; Shear Modulus: 8000000000; Thermal Expansion Coefficient: 0.00001; Young Modulus: 20999999488

# Material: Acciaio
Acciaio - Mass Density: 7850; Poisson Ratio: 0.3; Shear Modulus: 8000000000; Thermal Expansion Coefficient: 0.00001; Young Modulus: 20999999488

# Material: Acciaio
Acciaio - Mass Density: 7850; Poisson Ratio: 0.3; Shear Modulus: 8000000000; Thermal Expansion Coefficient: 0.00001; Young Modulus: 20999999488

# Material: Acciaio
Acciaio - Mass Density: 7850; Poisson Ratio: 0.3; Shear Modulus: 8000000000; Thermal Expansion Coefficient: 0.00001; Young Modulus: 20999999488

# Material: Acciaio
Acciaio - Mass Density: 7850; Poisson Ratio: 0.3; Shear Modulus: 8000000000; Thermal Expansion Coefficient: 0.00001; Young Modulus: 20999999488

# Material: Acciaio
Acciaio - Mass Density: 7850; Poisson Ratio: 0.3; Shear Modulus: 8000000000; Thermal Expansion Coefficient: 0.00001; Young Modulus: 20999999488

# Material: Acciaio
Acciaio - Mass Density: 7850; Poisson Ratio: 0.3; Shear Modulus: 8000000000; Thermal Expansion Coefficient: 0.00001; Young Modulus: 20999999488

# Material: Acciaio
Acciaio - Mass Density: 7850; Poisson Ratio: 0.3; Shear Modulus: 8000000000; Thermal Expansion Coefficient: 0.00001; Young Modulus: 20999999488

# Material: Acciaio
Acciaio - Mass Density: 7850; Poisson Ratio: 0.3; Shear Modulus: 8000000000; Thermal Expansion Coefficient: 0.00001; Young Modulus: 20999999488

# Material: Acciaio
Acciaio - Mass Density: 7850; Poisson Ratio: 0.3; Shear Modulus: 8000000000; Thermal Expansion Coefficient: 0.00001; Young Modulus: 20999999488

# Material: Acciaio
Acciaio - Mass Density: 7850; Poisson Ratio: 0.3; Shear Modulus: 8000000000; Thermal Expansion Coefficient: 0.00001; Young Modulus: 20999999488

# Material: Acciaio
Acciaio - Mass Density: 7850; Poisson Ratio: 0.3; Shear Modulus: 8000000000; Thermal Expansion Coefficient: 0.00001; Young Modulus: 20999999488

# Material: Acciaio
Acciaio - Mass Density: 7850; Poisson Ratio: 0.3; Shear Modulus: 8000000000; Thermal Expansion Coefficient: 0.00001; Young Modulus: 20999999488

# Material: Acciaio
Acciaio - Mass Density: 7850; Poisson Ratio: 0.3; Shear Modulus: 8000000000; Thermal Expansion Coefficient: 0.00001; Young Modulus: 20999999488

# Material: Acciaio
Acciaio - Mass Density: 7850; Poisson Ratio: 0.3; Shear Modulus: 8000000000; Thermal Expansion Coefficient: 0.00001; Young Modulus: 20999999488

# Material: Acciaio
Acciaio - Mass Density: 7850; Poisson Ratio: 0.3; Shear Modulus: 8000000000; Thermal Expansion Coefficient: 0.00001; Young Modulus: 20999999488

# Material: Acciaio
Acciaio - Mass Density: 7850; Poisson Ratio: 0.3; Shear Modulus: 8000000000; Thermal Expansion Coefficient: 0.00001; Young Modulus: 20999999488

# Material: Acciaio
Acciaio - Mass Density: 7850; Poisson Ratio: 0.3; Shear Modulus: 8000000000; Thermal Expansion Coefficient: 0.00001; Young Modulus: 20999999488

# Material: Acciaio
Acciaio - Mass Density: 7850; Poisson Ratio: 0.3; Shear Modulus: 8000000000; Thermal Expansion Coefficient: 0.00001; Young Modulus: 20999999488

# Material: Acciaio
Acciaio - Mass Density: 7850; Poisson Ratio: 0.3; Shear Modulus: 8000000000; Thermal Expansion Coefficient: 0.00001; Young Modulus: 20999999488

# Material: Acciaio
Acciaio - Mass Density: 7850; Poisson Ratio: 0.3; Shear Modulus: 8000000000; Thermal Expansion Coefficient: 0.00001; Young Modulus: 20999999488

# Material: Acciaio
Acciaio - Mass Density: 7850; Poisson Ratio: 0.3; Shear Modulus: 8000000000; Thermal Expansion Coefficient: 0.00001; Young Modulus: 20999999488

# Material: Acciaio
Acciaio - Mass Density: 7850; Poisson Ratio: 0.3; Shear Modulus: 8000000000; Thermal Expansion Coefficient: 0.00001; Young Modulus: 20999999488

# Material: Acciaio
Acciaio - Mass Density: 7850; Poisson Ratio: 0.3; Shear Modulus: 8000000000; Thermal Expansion Coefficient: 0.00001; Young Modulus: 20999999488

# Material: Acciaio
Acciaio - Mass Density: 7850; Poisson Ratio: 0.3; Shear Modulus: 8000000000; Thermal Expansion Coefficient: 0.00001; Young Modulus: 20999999488

# Material: Acciaio
Acciaio - Mass Density: 7850; Poisson Ratio: 0.3; Shear Modulus: 8000000000; Thermal Expansion Coefficient: 0.00001; Young Modulus: 20999999488

# Material: Acciaio
Acciaio - Mass Density: 7850; Poisson Ratio: 0.3; Shear Modulus: 8000000000; Thermal Expansion Coefficient: 0.00001; Young Modulus: 20999999488

# Material: Acciaio
Acciaio - Mass Density: 7850; Poisson Ratio: 0.3; Shear Modulus: 8000000000; Thermal Expansion Coefficient: 0.00001; Young Modulus: 20999999488

# Material: Acciaio
Acciaio - Mass Density: 7850; Poisson Ratio: 0.3; Shear Modulus: 8000000000; Thermal Expansion Coefficient: 0.00001; Young Modulus: 20999999488

# Material: Acciaio
Acciaio - Mass Density: 7850; Poisson Ratio: 0.3; Shear Modulus: 8000000000; Thermal Expansion Coefficient: 0.00001; Young Modulus: 20999999488

# Material: Acciaio
Acciaio - Mass Density: 7850; Poisson Ratio: 0.3; Shear Modulus: 8000000000; Thermal Expansion Coefficient: 0.00001; Young Modulus: 20999999488

# Material: Acciaio
Acciaio - Mass Density: 7850; Poisson Ratio: 0.3; Shear Modulus: 8000000000; Thermal Expansion Coefficient: 0.00001; Young Modulus: 20999999488

# Material: Acciaio
Acciaio - Mass Density: 7850; Poisson Ratio: 0.3; Shear Modulus: 8000000000; Thermal Expansion Coefficient: 0.00001; Young Modulus: 20999999488

# Material: Acciaio
Acciaio - Mass Density: 7850; Poisson Ratio: 0.3; Shear Modulus: 8000000000; Thermal Expansion Coefficient: 0.00001; Young Modulus: 20999999488

# Material: Acciaio
Acciaio - Mass Density: 7850; Poisson Ratio: 0.3; Shear Modulus: 8000000000; Thermal Expansion Coefficient: 0.00001; Young Modulus: 20999999488

# Material: Acciaio
Acciaio - Mass Density: 7850; Poisson Ratio: 0.3; Shear Modulus: 8000000000; Thermal Expansion Coefficient: 0.00001; Young Modulus: 20999999488

# Material: Acciaio
Acciaio - Mass Density: 7850; Poisson Ratio: 0.3; Shear Modulus: 8000000000; Thermal Expansion Coefficient: 0.00001; Young Modulus: 20999999488

# Material: Acciaio
Acciaio - Mass Density: 7850; Poisson Ratio: 0.3; Shear Modulus: 8000000000; Thermal Expansion Coefficient: 0.00001; Young Modulus: 20999999488

# Material: Acciaio
Acciaio - Mass Density: 7850; Poisson Ratio: 0.3; Shear Modulus: 8000000000; Thermal Expansion Coefficient: 0.00001; Young Modulus: 20999999488

# Material: Acciaio
Acciaio - Mass Density: 7850; Poisson Ratio: 0.3; Shear Modulus: 8000000000; Thermal Expansion Coefficient: 0.00001; Young Modulus: 20999999488

# Material: Acciaio
Acciaio - Mass Density: 7850; Poisson Ratio: 0.3; Shear Modulus: 8000000000; Thermal Expansion Coefficient: 0.00001; Young Modulus: 20999999488

# Material: Acciaio
Acciaio - Mass Density: 7850; Poisson Ratio: 0.3; Shear Modulus: 8000000000; Thermal Expansion Coefficient: 0.00001; Young Modulus: 20999999488

# Material: Acciaio
Acciaio - Mass Density: 7850; Poisson Ratio: 0.3; Shear Modulus: 8000000000; Thermal Expansion Coefficient: 0.00001; Young Modulus: 20999999488

# Material: Acciaio
Acciaio - Mass Density: 7850; Poisson Ratio: 0.3; Shear Modulus: 8000000000; Thermal Expansion Coefficient: 0.00001; Young Modulus: 20999999488

# Material: Acciaio
Acciaio - Mass Density: 7850; Poisson Ratio: 0.3; Shear Modulus: 8000000000; Thermal Expansion Coefficient: 0.00001; Young Modulus: 20999999488

# Material: Acciaio
Acciaio - Mass Density: 7850; Poisson Ratio: 0.3; Shear Modulus: 8000000000; Thermal Expansion Coefficient: 0.00001; Young Modulus: 20999999488

# Material: Acciaio
Acciaio - Mass Density: 7850; Poisson Ratio: 0.3; Shear Modulus: 8000000000; Thermal Expansion Coefficient: 0.00001; Young Modulus: 20999999488

# Material: Acciaio
Acciaio - Mass Density: 7850; Poisson Ratio: 0.3; Shear Modulus: 8000000000; Thermal Expansion Coefficient: 0.00001; Young Modulus: 20999999488

# Material: Acciaio
Acciaio - Mass Density: 7850; Poisson Ratio: 0.3; Shear Modulus: 8000000000; Thermal Expansion Coefficient: 0.00001; Young Modulus: 20999999488

# Material: Acciaio
Acciaio - Mass Density: 7850; Poisson Ratio: 0.3; Shear Modulus: 8000000000; Thermal Expansion Coefficient: 0.00001; Young Modulus: 20999999488

# Material: Acciaio
Acciaio - Mass Density: 7850; Poisson Ratio: 0.3; Shear Modulus: 8000000000; Thermal Expansion Coefficient: 0.00001; Young Modulus: 20999999488

# Material: Acciaio
Acciaio - Mass Density: 7850; Poisson Ratio: 0.3; Shear Modulus: 8000000000; Thermal Expansion Coefficient: 0.00001; Young Modulus: 20999999488

# Material: Acciaio
Acciaio - Mass Density: 7850; Poisson Ratio: 0.3; Shear Modulus: 8000000000; Thermal Expansion Coefficient: 0.00001; Young Modulus: 20999999488

# Material: Acciaio
Acciaio - Mass Density: 7850; Poisson Ratio: 0.3; Shear Modulus: 8000000000; Thermal Expansion Coefficient: 0.00001; Young Modulus: 20999999488

# Material: Acciaio
Acciaio - Mass Density: 7850; Poisson Ratio: 0.3; Shear Modulus: 8000000000; Thermal Expansion Coefficient: 0.00001; Young Modulus: 20999999488

# Material: Acciaio
Acciaio - Mass Density: 7850; Poisson Ratio: 0.3; Shear Modulus: 8000000000; Thermal Expansion Coefficient: 0.00001; Young Modulus: 20999999488

# Material: Acciaio
Acciaio - Mass Density: 7850; Poisson Ratio: 0.3; Shear Modulus: 8000000000; Thermal Expansion Coefficient: 0.00001; Young Modulus: 20999999488

# Material: Acciaio
Acciaio - Mass Density: 7850; Poisson Ratio: 0.3; Shear Modulus: 8000000000; Thermal Expansion Coefficient: 0.00001; Young Modulus: 20999999488

# Material: Acciaio
Acciaio - Mass Density: 7850; Poisson Ratio: 0.3; Shear Modulus: 8000000000; Thermal Expansion Coefficient: 0.00001; Young Modulus: 20999999488

# Material: Acciaio
Acciaio - Mass Density: 7850; Poisson Ratio: 0.3; Shear Modulus: 8000000000; Thermal Expansion Coefficient: 0.00001; Young Modulus: 20999999488

# Material: Acciaio
Acciaio - Mass Density: 7850; Poisson Ratio: 0.3; Shear Modulus: 8000000000; Thermal Expansion Coefficient: 0.00001; Young Modulus: 20999999488

# Material: Acciaio
Acciaio - Mass Density: 7850; Poisson Ratio: 0.3; Shear Modulus: 8000000000; Thermal Expansion Coefficient: 0.00001; Young Modulus: 20999999488

# Material: Acciaio
Acciaio - Mass Density: 7850; Poisson Ratio: 0.3; Shear Modulus: 8000000000; Thermal Expansion Coefficient: 0.00001; Young Modulus: 20999999488

# Material: Acciaio
Acciaio - Mass Density: 7850; Poisson Ratio: 0.3; Shear Modulus: 8000000000; Thermal Expansion Coefficient: 0.00001; Young Modulus: 20999999488

# Material: Acciaio
Acciaio - Mass Density: 7850; Poisson Ratio: 0.3; Shear Modulus: 8000000000; Thermal Expansion Coefficient: 0.00001; Young Modulus: 20999999488

# Material: Acciaio
Acciaio - Mass Density: 7850; Poisson Ratio: 0.3; Shear Modulus: 8000000000; Thermal Expansion Coefficient: 0.00001; Young Modulus: 20999999488

# Material: Acciaio
Acciaio - Mass Density: 7850; Poisson Ratio: 0.3; Shear Modulus: 8000000000; Thermal Expansion Coefficient: 0.00001; Young Modulus: 20999999488

# Material: Acciaio
Acciaio - Mass Density: 7850; Poisson Ratio: 0.3; Shear Modulus: 8000000000; Thermal Expansion Coefficient: 0.00001; Young Modulus: 20999999488

# Material: Acciaio
Acciaio - Mass Density: 7850; Poisson Ratio: 0.3; Shear Modulus: 8000000000; Thermal Expansion Coefficient: 0.00001; Young Modulus: 20999999488

# Material: Acciaio
Acciaio - Mass Density: 7850; Poisson Ratio: 0.3; Shear Modulus: 8000000000; Thermal Expansion Coefficient: 0.00001; Young Modulus: 20999999488

# Material: Acciaio
Acciaio - Mass Density: 7850; Poisson Ratio: 0.3; Shear Modulus: 8000000000; Thermal Expansion Coefficient: 0.00001; Young Modulus: 20999999488

# Material: Acciaio
Acciaio - Mass Density: 7850; Poisson Ratio: 0.3; Shear Modulus: 8000000000; Thermal Expansion Coefficient: 0.00001; Young Modulus: 20999999488

# Material: Acciaio
Acciaio - Mass Density: 7850; Poisson Ratio: 0.3; Shear Modulus: 8000000000; Thermal Expansion Coefficient: 0.00001; Young Modulus: 20999999488

# Material: Acciaio
Acciaio - Mass Density: 7850; Poisson Ratio: 0.3; Shear Modulus: 8000000000; Thermal Expansion Coefficient: 0.00001; Young Modulus: 20999999488

# Material: Acciaio
Acciaio - Mass Density: 7850; Poisson Ratio: 0.3; Shear Modulus: 8000000000; Thermal Expansion Coefficient: 0.00001; Young Modulus: 20999999488

# Material: Acciaio
Acciaio - Mass Density: 7850; Poisson Ratio: 0.3; Shear Modulus: 8000000000; Thermal Expansion Coefficient: 0.00001; Young Modulus: 20999999488

# Material: Acciaio
Acciaio - Mass Density: 7850; Poisson Ratio: 0.3; Shear Modulus: 8000000000; Thermal Expansion Coefficient: 0.00001; Young Modulus: 20999999488

# Material: Acciaio
Acciaio - Mass Density: 7850; Poisson Ratio: 0.3; Shear Modulus: 8000000000; Thermal Expansion Coefficient: 0.00001; Young Modulus: 20999999488

# Material: Acciaio
Acciaio - Mass Density: 7850; Poisson Ratio: 0.3; Shear Modulus: 8000000000; Thermal Expansion Coefficient: 0.00001; Young Modulus: 20999999488

# Material: Acciaio
Acciaio - Mass Density: 7850; Poisson Ratio: 0.3; Shear Modulus: 8000000000; Thermal Expansion Coefficient: 0.00001; Young Modulus: 20999999488

# Material: Acciaio
Acciaio - Mass Density: 7850; Poisson Ratio: 0.3; Shear Modulus: 8000000000; Thermal Expansion Coefficient: 0.00001; Young Modulus: 20999999488

# Material: Acciaio
Acciaio - Mass Density: 7850; Poisson Ratio: 0.3; Shear Modulus: 8000000000; Thermal Expansion Coefficient: 0.00001; Young Modulus: 20999999488

# Material: Acciaio
Acciaio - Mass Density: 7850; Poisson Ratio: 0.3; Shear Modulus: 8000000000; Thermal Expansion Coefficient: 0.00001; Young Modulus: 20999999488

# Material: Acciaio
Acciaio - Mass Density: 7850; Poisson Ratio: 0.3; Shear Modulus: 8000000000; Thermal Expansion Coefficient: 0.00001; Young Modulus: 20999999488

# Material: Acciaio
Acciaio - Mass Density: 7850; Poisson Ratio: 0.3; Shear Modulus: 8000000000; Thermal Expansion Coefficient: 0.00001; Young Modulus: 20999999488

# Material: Acciaio
Acciaio - Mass Density: 7850; Poisson Ratio: 0.3; Shear Modulus: 8000000000; Thermal Expansion Coefficient: 0.00001; Young Modulus: 20999999488

# Material: Acciaio
Acciaio - Mass Density: 7850; Poisson Ratio: 0.3; Shear Modulus: 8000000000; Thermal Expansion Coefficient: 0.00001; Young Modulus: 20999999488

# Material: Acciaio
Acciaio - Mass Density: 7850; Poisson Ratio: 0.3; Shear Modulus: 8000000000; Thermal Expansion Coefficient: 0.00001; Young Modulus: 20999999488

# Material: Acciaio
Acciaio - Mass Density: 7850; Poisson Ratio: 0.3; Shear Modulus: 8000000000; Thermal Expansion Coefficient: 0.00001; Young Modulus: 20999999488

# Material: Acciaio
Acciaio - Mass Density: 7850; Poisson Ratio: 0.3; Shear Modulus: 8000000000; Thermal Expansion Coefficient: 0.00001; Young Modulus: 20999999488

# Material: Acciaio
Acciaio - Mass Density: 7850; Poisson Ratio: 0.3; Shear Modulus: 8000000000; Thermal Expansion Coefficient: 0.00001; Young Modulus: 20999999488

# Material: Acciaio
